One B-rep face of a CAD part: STEP entity #255.
In plain terms, the planar face has unit normal (0, -1, 0).
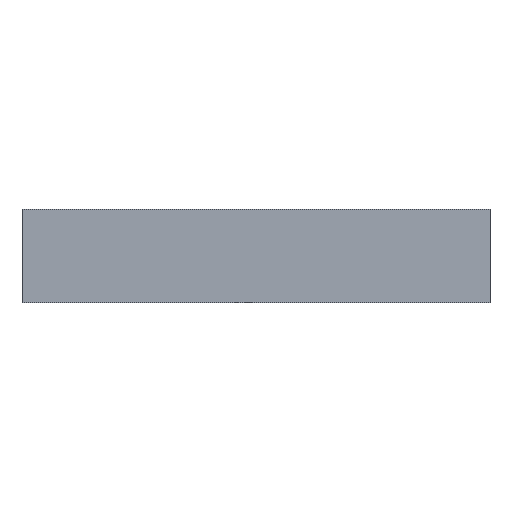
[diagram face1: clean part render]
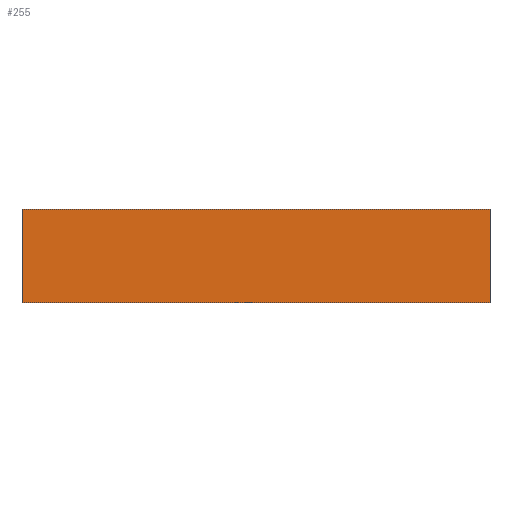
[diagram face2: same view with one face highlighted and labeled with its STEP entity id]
Its self-contained STEP definition (entity closure, numbers rounded to 3 decimals):
#39 = EDGE_CURVE('',#40,#42,#44,.T.);
#40 = VERTEX_POINT('',#41);
#41 = CARTESIAN_POINT('',(-35.,19.5,38.2));
#42 = VERTEX_POINT('',#43);
#43 = CARTESIAN_POINT('',(-35.,19.5,38.4));
#44 = SURFACE_CURVE('',#45,(#49,#61),.PCURVE_S1.);
#45 = LINE('',#46,#47);
#46 = CARTESIAN_POINT('',(-35.,19.5,38.2));
#47 = VECTOR('',#48,1.);
#48 = DIRECTION('',(0.,0.,1.));
#49 = PCURVE('',#50,#55);
#50 = PLANE('',#51);
#51 = AXIS2_PLACEMENT_3D('',#52,#53,#54);
#52 = CARTESIAN_POINT('',(-35.,19.5,38.2));
#53 = DIRECTION('',(1.,0.,0.));
#54 = DIRECTION('',(0.,0.,1.));
#55 = DEFINITIONAL_REPRESENTATION('',(#56),#60);
#56 = LINE('',#57,#58);
#57 = CARTESIAN_POINT('',(0.,0.));
#58 = VECTOR('',#59,1.);
#59 = DIRECTION('',(1.,0.));
#60 = ( GEOMETRIC_REPRESENTATION_CONTEXT(2) 
PARAMETRIC_REPRESENTATION_CONTEXT() REPRESENTATION_CONTEXT('2D SPACE',''
  ) );
#61 = PCURVE('',#62,#67);
#62 = PLANE('',#63);
#63 = AXIS2_PLACEMENT_3D('',#64,#65,#66);
#64 = CARTESIAN_POINT('',(-35.,19.5,38.2));
#65 = DIRECTION('',(0.,1.,0.));
#66 = DIRECTION('',(0.,0.,1.));
#67 = DEFINITIONAL_REPRESENTATION('',(#68),#72);
#68 = LINE('',#69,#70);
#69 = CARTESIAN_POINT('',(0.,0.));
#70 = VECTOR('',#71,1.);
#71 = DIRECTION('',(1.,0.));
#72 = ( GEOMETRIC_REPRESENTATION_CONTEXT(2) 
PARAMETRIC_REPRESENTATION_CONTEXT() REPRESENTATION_CONTEXT('2D SPACE',''
  ) );
#90 = PLANE('',#91);
#91 = AXIS2_PLACEMENT_3D('',#92,#93,#94);
#92 = CARTESIAN_POINT('',(-35.,19.5,38.2));
#93 = DIRECTION('',(0.,0.,1.));
#94 = DIRECTION('',(1.,0.,0.));
#144 = PLANE('',#145);
#145 = AXIS2_PLACEMENT_3D('',#146,#147,#148);
#146 = CARTESIAN_POINT('',(-35.,19.5,38.4));
#147 = DIRECTION('',(0.,0.,1.));
#148 = DIRECTION('',(1.,0.,0.));
#159 = EDGE_CURVE('',#160,#162,#164,.T.);
#160 = VERTEX_POINT('',#161);
#161 = CARTESIAN_POINT('',(-34.,19.5,38.2));
#162 = VERTEX_POINT('',#163);
#163 = CARTESIAN_POINT('',(-34.,19.5,38.4));
#164 = SURFACE_CURVE('',#165,(#169,#181),.PCURVE_S1.);
#165 = LINE('',#166,#167);
#166 = CARTESIAN_POINT('',(-34.,19.5,38.2));
#167 = VECTOR('',#168,1.);
#168 = DIRECTION('',(0.,0.,1.));
#169 = PCURVE('',#170,#175);
#170 = PLANE('',#171);
#171 = AXIS2_PLACEMENT_3D('',#172,#173,#174);
#172 = CARTESIAN_POINT('',(-34.,19.5,38.2));
#173 = DIRECTION('',(1.,0.,0.));
#174 = DIRECTION('',(0.,0.,1.));
#175 = DEFINITIONAL_REPRESENTATION('',(#176),#180);
#176 = LINE('',#177,#178);
#177 = CARTESIAN_POINT('',(0.,0.));
#178 = VECTOR('',#179,1.);
#179 = DIRECTION('',(1.,0.));
#180 = ( GEOMETRIC_REPRESENTATION_CONTEXT(2) 
PARAMETRIC_REPRESENTATION_CONTEXT() REPRESENTATION_CONTEXT('2D SPACE',''
  ) );
#181 = PCURVE('',#62,#182);
#182 = DEFINITIONAL_REPRESENTATION('',(#183),#187);
#183 = LINE('',#184,#185);
#184 = CARTESIAN_POINT('',(0.,1.));
#185 = VECTOR('',#186,1.);
#186 = DIRECTION('',(1.,0.));
#187 = ( GEOMETRIC_REPRESENTATION_CONTEXT(2) 
PARAMETRIC_REPRESENTATION_CONTEXT() REPRESENTATION_CONTEXT('2D SPACE',''
  ) );
#255 = ADVANCED_FACE('',(#256),#62,.F.);
#256 = FACE_BOUND('',#257,.F.);
#257 = EDGE_LOOP('',(#258,#279,#280,#301));
#258 = ORIENTED_EDGE('',*,*,#259,.F.);
#259 = EDGE_CURVE('',#40,#160,#260,.T.);
#260 = SURFACE_CURVE('',#261,(#265,#272),.PCURVE_S1.);
#261 = LINE('',#262,#263);
#262 = CARTESIAN_POINT('',(-35.,19.5,38.2));
#263 = VECTOR('',#264,1.);
#264 = DIRECTION('',(1.,0.,0.));
#265 = PCURVE('',#62,#266);
#266 = DEFINITIONAL_REPRESENTATION('',(#267),#271);
#267 = LINE('',#268,#269);
#268 = CARTESIAN_POINT('',(0.,0.));
#269 = VECTOR('',#270,1.);
#270 = DIRECTION('',(0.,1.));
#271 = ( GEOMETRIC_REPRESENTATION_CONTEXT(2) 
PARAMETRIC_REPRESENTATION_CONTEXT() REPRESENTATION_CONTEXT('2D SPACE',''
  ) );
#272 = PCURVE('',#90,#273);
#273 = DEFINITIONAL_REPRESENTATION('',(#274),#278);
#274 = LINE('',#275,#276);
#275 = CARTESIAN_POINT('',(0.,0.));
#276 = VECTOR('',#277,1.);
#277 = DIRECTION('',(1.,0.));
#278 = ( GEOMETRIC_REPRESENTATION_CONTEXT(2) 
PARAMETRIC_REPRESENTATION_CONTEXT() REPRESENTATION_CONTEXT('2D SPACE',''
  ) );
#279 = ORIENTED_EDGE('',*,*,#39,.T.);
#280 = ORIENTED_EDGE('',*,*,#281,.T.);
#281 = EDGE_CURVE('',#42,#162,#282,.T.);
#282 = SURFACE_CURVE('',#283,(#287,#294),.PCURVE_S1.);
#283 = LINE('',#284,#285);
#284 = CARTESIAN_POINT('',(-35.,19.5,38.4));
#285 = VECTOR('',#286,1.);
#286 = DIRECTION('',(1.,0.,0.));
#287 = PCURVE('',#62,#288);
#288 = DEFINITIONAL_REPRESENTATION('',(#289),#293);
#289 = LINE('',#290,#291);
#290 = CARTESIAN_POINT('',(0.2,0.));
#291 = VECTOR('',#292,1.);
#292 = DIRECTION('',(0.,1.));
#293 = ( GEOMETRIC_REPRESENTATION_CONTEXT(2) 
PARAMETRIC_REPRESENTATION_CONTEXT() REPRESENTATION_CONTEXT('2D SPACE',''
  ) );
#294 = PCURVE('',#144,#295);
#295 = DEFINITIONAL_REPRESENTATION('',(#296),#300);
#296 = LINE('',#297,#298);
#297 = CARTESIAN_POINT('',(0.,0.));
#298 = VECTOR('',#299,1.);
#299 = DIRECTION('',(1.,0.));
#300 = ( GEOMETRIC_REPRESENTATION_CONTEXT(2) 
PARAMETRIC_REPRESENTATION_CONTEXT() REPRESENTATION_CONTEXT('2D SPACE',''
  ) );
#301 = ORIENTED_EDGE('',*,*,#159,.F.);
